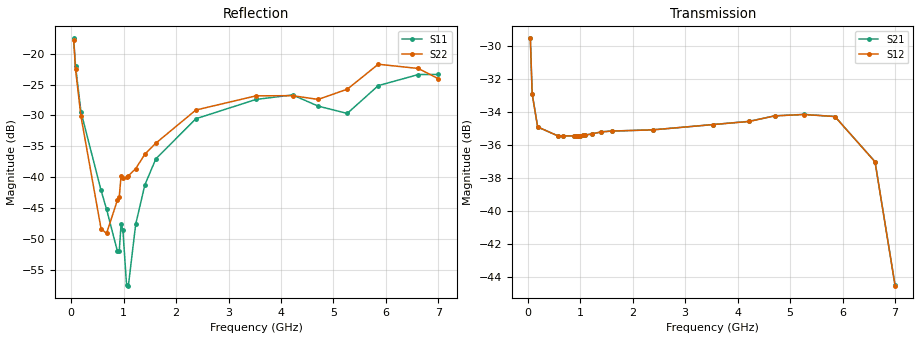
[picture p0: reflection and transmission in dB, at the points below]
! Integrated Device Technology
! Corporate Headquarters
! 6024 Silver Creek Valley Road
! San Jose, CA 95138  USA
! Phone:  1-408-284-8200
! Toll Free:  1-800-223-1366
! Webpage:  http://www.idt.com/
! Timing and RF Division
! 515 Groton Road, Suite 102
! Westford, MA 01886-6024
! Device:  F2258
! Description: Voltage Variable RF Attenuator
! Frequency:  50.0 -  6000.00 MHz
! Package:  3x3 mm Thin QFN Plastic Package: 16 pin
! Ports:  2 RF, 2 DC
!  Pin  1  = NC
!  Pin  2  = NC
!  Pin  3  = RF2  = Port 2
!  Pin  4  = GND
!  Pin  5  = Vdd
!  Pin  6  = NC
!  Pin  7  = VCTRL
!  Pin  8  = NC
!  Pin  9  = GND
!  Pin 10  = RF1  = Port 1
!  Pin 11  = NC
!  Pin 12  = NC
!  Pin 13  = NC
!  Pin 14  = NC
!  Pin 15  = NC
!  Pin 16  = NC
! Vcntrl:  2.290 Volts
! Vdd:  +3.300 Volts
! Current:  1.150 mA
! Data:  The device was measured on a the F2258 evaluation board which has
!  individual transmission lines to the RF pins.  Data was collected
!  using a calibrated network analyzer.  The evaluation board was
!  de-embedded using a TRL calibration technique.
!  The reference plane is the edge of the package pin.
! Misc:  SN 10
!  Action Tracker AT0285
! Date Measured:  2014-12-10
! Date:  2016-01-13  MJV
! Note:
!  Integrated Device Technology supplies this data as a sample of measured
!  data at the package pin for this product.  Your particular data for this
!  product may vary.
!  Data was taken at 25 degrees C.
!  Integrated Device Technology reserves the right to change this data at anytime.
!Freq_(GHz)  S11M_(dB)  S11P_(deg)  S21M_(dB)  S21P_(deg)  S12M_(dB)  S12P_(deg)  S22M_(dB)  S22P_(deg)
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# GHz S dB R 50
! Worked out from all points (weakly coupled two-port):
!   201 points, 50 MHz to 7 GHz, reference 50 ohm
!   highest |S21| = -29.52 dB at 50 MHz (marker M1); lowest = -44.5 dB at 7 GHz (marker M2)
!   lowest |S11| = -57.5 dB at 1.093 GHz (marker M3), VSWR 1.00, Z = 49.9 + j0.114 ohm
!   |S11| at or under -10 dB: start of sweep to end of sweep
!   |S22| runs from -49.2 to -17.8 dB; largest |S21 - S12| = 7e-05
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0.05  -17.55 -111.0  -29.52 -68.5  -29.52 -68.5  -17.84 -111.4
0.08475  -21.98 -107.5  -32.88 -48.8  -32.89 -48.7  -22.50 -107.6
0.189  -29.42 -109.5  -34.89 -24.7  -34.89 -24.8  -30.15 -110.0
0.57125  -42.07 -124.9  -35.43 -10.3  -35.43 -10.4  -48.27 -164.9
0.6755  -45.11 -131.9  -35.44 -9.4  -35.44 -9.4  -49.05 146.5
0.884  -51.94 166.2  -35.44 -8.4  -35.44 -8.4  -43.65 118.6
0.91875  -51.86 150.9  -35.43 -8.3  -35.43 -8.3  -43.10 116.7
0.9535  -47.47 -162.8  -35.44 -8.2  -35.45 -8.2  -39.73 122.6
0.98825  -48.56 -174.5  -35.42 -8.1  -35.43 -8.1  -40.08 120.2
1.05775  -57.41 154.9  -35.41 -7.9  -35.40 -7.9  -39.96 105.8
1.0925  -57.48 121.2  -35.39 -7.9  -35.39 -7.9  -39.74 101.7
1.2315  -47.57 46.8  -35.31 -7.9  -35.31 -7.9  -38.59 80.2
1.40525  -41.24 33.8  -35.19 -8.5  -35.19 -8.5  -36.27 66.6
1.61375  -37.02 32.9  -35.14 -9.6  -35.14 -9.6  -34.48 53.8
2.37825  -30.53 48.1  -35.07 -13.2  -35.07 -13.2  -29.12 43.6
3.525  -27.41 91.6  -34.75 -19.6  -34.75 -19.6  -26.83 67.6
4.22  -26.68 105.2  -34.55 -24.3  -34.56 -24.3  -26.80 75.3
4.7065  -28.48 95.6  -34.22 -28.7  -34.22 -28.6  -27.41 58.8
5.2625  -29.67 54.4  -34.13 -34.8  -34.14 -34.9  -25.76 21.5
5.85325  -25.18 29.9  -34.26 -45.5  -34.26 -45.5  -21.73 -2.4
6.61775  -23.39 49.7  -37.00 -68.7  -37.01 -68.6  -22.41 -44.2
7  -23.37 84.5  -44.50 -61.5  -44.52 -61.1  -24.08 -130.0
